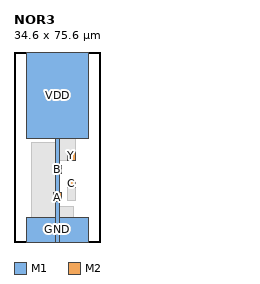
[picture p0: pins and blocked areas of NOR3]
MACRO NOR3
  CLASS CORE ;
  ORIGIN 0 0 ;
  SIZE 34.600 BY 75.600 ;
  SYMMETRY X Y ;
  SITE TR1um_access_site ;
  PIN VDD
    DIRECTION INOUT ;
    USE POWER ;
    PORT
      LAYER M1 ;
        RECT 16.400 0.000 18.200 41.000 ;
      LAYER M1 ;
        RECT 5.000 41.000 29.600 75.600 ;
    END
  END VDD
  PIN GND
    DIRECTION INOUT ;
    USE GROUND ;
    PORT
      LAYER M1 ;
        RECT 5.000 0.000 29.600 9.800 ;
    END
  END GND
  PIN A
    DIRECTION INPUT ;
    USE SIGNAL ;
    PORT
      LAYER M2 ;
        RECT 15.600 16.100 19.000 19.500 ;
    END
  END A
  PIN B
    DIRECTION INPUT ;
    USE SIGNAL ;
    PORT
      LAYER M2 ;
        RECT 15.600 27.100 19.000 30.500 ;
    END
  END B
  PIN C
    DIRECTION INPUT ;
    USE SIGNAL ;
    PORT
      LAYER M2 ;
        RECT 21.100 21.600 24.500 25.000 ;
    END
  END C
  PIN Y
    DIRECTION OUTPUT ;
    USE SIGNAL ;
    PORT
      LAYER M2 ;
        RECT 21.100 32.600 24.500 36.000 ;
    END
  END Y
  OBS
    LAYER M1 ;
      RECT 18.200 6.400 23.700 14.100 ;
    LAYER M1 ;
      RECT 15.600 16.100 16.400 19.500 ;
    LAYER M1 ;
      RECT 18.200 16.100 19.000 19.500 ;
    LAYER M1 ;
      RECT 12.600 21.300 16.400 23.900 ;
    LAYER M1 ;
      RECT 21.100 16.500 24.500 25.000 ;
    LAYER M1 ;
      RECT 15.600 27.100 16.400 30.500 ;
    LAYER M1 ;
      RECT 18.200 27.100 19.000 30.500 ;
    LAYER M1 ;
      RECT 10.400 33.100 16.400 35.700 ;
    LAYER M1 ;
      RECT 7.100 6.400 16.400 39.500 ;
    LAYER M1 ;
      RECT 13.100 41.000 15.700 51.200 ;
    LAYER M1 ;
      RECT 17.100 41.000 19.700 51.200 ;
    LAYER M1 ;
      RECT 18.200 32.600 24.500 51.200 ;
    LAYER V1 ;
      RECT 16.600 17.100 18.000 18.500 ;
    LAYER V1 ;
      RECT 22.100 22.600 23.500 24.000 ;
    LAYER V1 ;
      RECT 16.600 28.100 18.000 29.500 ;
    LAYER V1 ;
      RECT 22.100 33.600 23.500 35.000 ;
  END
END NOR3
